VERSION 5.7 ;
  NOWIREEXTENSIONATPIN ON ;
  DIVIDERCHAR "/" ;
  BUSBITCHARS "[]" ;
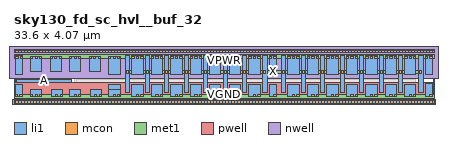
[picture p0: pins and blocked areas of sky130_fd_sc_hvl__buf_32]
MACRO sky130_fd_sc_hvl__buf_32
  CLASS BLOCK ;
  FOREIGN sky130_fd_sc_hvl__buf_32 ;
  ORIGIN 0.000 0.000 ;
  SIZE 33.600 BY 4.070 ;
  PIN A
    ANTENNAGATEAREA 11.250000 ;
    PORT
      LAYER li1 ;
        RECT 0.220 1.580 4.630 1.815 ;
    END
  END A
  PIN VGND
    USE GROUND ;
    PORT
      LAYER li1 ;
        RECT 0.110 0.425 0.645 1.410 ;
        RECT 7.580 1.025 8.480 1.395 ;
        RECT 1.340 0.415 2.230 1.025 ;
        RECT 2.960 0.425 3.855 1.025 ;
        RECT 4.440 0.425 5.330 1.025 ;
        RECT 6.080 0.425 6.975 1.025 ;
        RECT 7.560 0.425 8.480 1.025 ;
        RECT 9.430 0.425 10.320 1.395 ;
        RECT 10.990 0.425 11.880 1.395 ;
        RECT 12.550 0.425 13.440 1.395 ;
        RECT 14.110 0.425 15.000 1.395 ;
        RECT 15.670 0.425 16.560 1.395 ;
        RECT 17.230 0.425 18.120 1.395 ;
        RECT 18.790 0.425 19.680 1.395 ;
        RECT 20.430 0.425 20.960 1.395 ;
        RECT 21.910 0.425 22.800 1.395 ;
        RECT 23.470 0.425 24.360 1.395 ;
        RECT 25.030 0.425 25.920 1.395 ;
        RECT 26.590 0.425 27.480 1.395 ;
        RECT 28.150 0.425 29.040 1.395 ;
        RECT 29.710 0.425 30.600 1.395 ;
        RECT 31.270 0.425 32.160 1.395 ;
        RECT 32.910 0.425 33.440 1.495 ;
      LAYER mcon ;
        RECT 0.115 0.425 0.285 0.595 ;
        RECT 0.475 0.425 0.645 0.595 ;
        RECT 1.340 0.425 1.510 0.595 ;
        RECT 1.700 0.425 1.870 0.595 ;
        RECT 2.060 0.425 2.230 0.595 ;
        RECT 3.320 0.425 3.490 0.595 ;
        RECT 3.680 0.425 3.850 0.595 ;
        RECT 4.800 0.425 4.970 0.595 ;
        RECT 5.160 0.425 5.330 0.595 ;
        RECT 6.440 0.425 6.610 0.595 ;
        RECT 6.800 0.425 6.970 0.595 ;
        RECT 7.920 0.425 8.090 0.595 ;
        RECT 8.280 0.425 8.450 0.595 ;
        RECT 9.790 0.425 9.960 0.595 ;
        RECT 10.150 0.425 10.320 0.595 ;
        RECT 11.350 0.425 11.520 0.595 ;
        RECT 11.710 0.425 11.880 0.595 ;
        RECT 12.910 0.425 13.080 0.595 ;
        RECT 13.270 0.425 13.440 0.595 ;
        RECT 14.470 0.425 14.640 0.595 ;
        RECT 14.830 0.425 15.000 0.595 ;
        RECT 16.030 0.425 16.200 0.595 ;
        RECT 16.390 0.425 16.560 0.595 ;
        RECT 17.590 0.425 17.760 0.595 ;
        RECT 17.950 0.425 18.120 0.595 ;
        RECT 19.150 0.425 19.320 0.595 ;
        RECT 19.510 0.425 19.680 0.595 ;
        RECT 20.790 0.425 20.960 0.595 ;
        RECT 22.270 0.425 22.440 0.595 ;
        RECT 22.630 0.425 22.800 0.595 ;
        RECT 23.830 0.425 24.000 0.595 ;
        RECT 24.190 0.425 24.360 0.595 ;
        RECT 25.390 0.425 25.560 0.595 ;
        RECT 25.750 0.425 25.920 0.595 ;
        RECT 26.950 0.425 27.120 0.595 ;
        RECT 27.310 0.425 27.480 0.595 ;
        RECT 28.510 0.425 28.680 0.595 ;
        RECT 28.870 0.425 29.040 0.595 ;
        RECT 30.070 0.425 30.240 0.595 ;
        RECT 30.430 0.425 30.600 0.595 ;
        RECT 31.630 0.425 31.800 0.595 ;
        RECT 31.990 0.425 32.160 0.595 ;
        RECT 33.270 0.425 33.440 0.595 ;
      LAYER met1 ;
        RECT 0.000 0.255 33.600 0.625 ;
    END
  END VGND
  PIN VNB
    ANTENNADIFFAREA 5.712000 ;
    PORT
      LAYER pwell ;
        RECT 0.020 0.215 33.530 1.585 ;
        RECT -0.130 -0.215 33.730 0.215 ;
      LAYER li1 ;
        RECT 0.000 -0.085 33.600 0.085 ;
      LAYER mcon ;
        RECT 0.155 -0.085 0.325 0.085 ;
        RECT 0.635 -0.085 0.805 0.085 ;
        RECT 1.115 -0.085 1.285 0.085 ;
        RECT 1.595 -0.085 1.765 0.085 ;
        RECT 2.075 -0.085 2.245 0.085 ;
        RECT 2.555 -0.085 2.725 0.085 ;
        RECT 3.035 -0.085 3.205 0.085 ;
        RECT 3.515 -0.085 3.685 0.085 ;
        RECT 3.995 -0.085 4.165 0.085 ;
        RECT 4.475 -0.085 4.645 0.085 ;
        RECT 4.955 -0.085 5.125 0.085 ;
        RECT 5.435 -0.085 5.605 0.085 ;
        RECT 5.915 -0.085 6.085 0.085 ;
        RECT 6.395 -0.085 6.565 0.085 ;
        RECT 6.875 -0.085 7.045 0.085 ;
        RECT 7.355 -0.085 7.525 0.085 ;
        RECT 7.835 -0.085 8.005 0.085 ;
        RECT 8.315 -0.085 8.485 0.085 ;
        RECT 8.795 -0.085 8.965 0.085 ;
        RECT 9.275 -0.085 9.445 0.085 ;
        RECT 9.755 -0.085 9.925 0.085 ;
        RECT 10.235 -0.085 10.405 0.085 ;
        RECT 10.715 -0.085 10.885 0.085 ;
        RECT 11.195 -0.085 11.365 0.085 ;
        RECT 11.675 -0.085 11.845 0.085 ;
        RECT 12.155 -0.085 12.325 0.085 ;
        RECT 12.635 -0.085 12.805 0.085 ;
        RECT 13.115 -0.085 13.285 0.085 ;
        RECT 13.595 -0.085 13.765 0.085 ;
        RECT 14.075 -0.085 14.245 0.085 ;
        RECT 14.555 -0.085 14.725 0.085 ;
        RECT 15.035 -0.085 15.205 0.085 ;
        RECT 15.515 -0.085 15.685 0.085 ;
        RECT 15.995 -0.085 16.165 0.085 ;
        RECT 16.475 -0.085 16.645 0.085 ;
        RECT 16.955 -0.085 17.125 0.085 ;
        RECT 17.435 -0.085 17.605 0.085 ;
        RECT 17.915 -0.085 18.085 0.085 ;
        RECT 18.395 -0.085 18.565 0.085 ;
        RECT 18.875 -0.085 19.045 0.085 ;
        RECT 19.355 -0.085 19.525 0.085 ;
        RECT 19.835 -0.085 20.005 0.085 ;
        RECT 20.315 -0.085 20.485 0.085 ;
        RECT 20.795 -0.085 20.965 0.085 ;
        RECT 21.275 -0.085 21.445 0.085 ;
        RECT 21.755 -0.085 21.925 0.085 ;
        RECT 22.235 -0.085 22.405 0.085 ;
        RECT 22.715 -0.085 22.885 0.085 ;
        RECT 23.195 -0.085 23.365 0.085 ;
        RECT 23.675 -0.085 23.845 0.085 ;
        RECT 24.155 -0.085 24.325 0.085 ;
        RECT 24.635 -0.085 24.805 0.085 ;
        RECT 25.115 -0.085 25.285 0.085 ;
        RECT 25.595 -0.085 25.765 0.085 ;
        RECT 26.075 -0.085 26.245 0.085 ;
        RECT 26.555 -0.085 26.725 0.085 ;
        RECT 27.035 -0.085 27.205 0.085 ;
        RECT 27.515 -0.085 27.685 0.085 ;
        RECT 27.995 -0.085 28.165 0.085 ;
        RECT 28.475 -0.085 28.645 0.085 ;
        RECT 28.955 -0.085 29.125 0.085 ;
        RECT 29.435 -0.085 29.605 0.085 ;
        RECT 29.915 -0.085 30.085 0.085 ;
        RECT 30.395 -0.085 30.565 0.085 ;
        RECT 30.875 -0.085 31.045 0.085 ;
        RECT 31.355 -0.085 31.525 0.085 ;
        RECT 31.835 -0.085 32.005 0.085 ;
        RECT 32.315 -0.085 32.485 0.085 ;
        RECT 32.795 -0.085 32.965 0.085 ;
        RECT 33.275 -0.085 33.445 0.085 ;
      LAYER met1 ;
        RECT 0.000 -0.115 33.600 0.115 ;
    END
  END VNB
  PIN VPB
    ANTENNADIFFAREA 5.712000 ;
    PORT
      LAYER nwell ;
        RECT -0.330 1.885 33.930 4.485 ;
      LAYER li1 ;
        RECT 0.000 3.985 33.600 4.155 ;
      LAYER mcon ;
        RECT 0.155 3.985 0.325 4.155 ;
        RECT 0.635 3.985 0.805 4.155 ;
        RECT 1.115 3.985 1.285 4.155 ;
        RECT 1.595 3.985 1.765 4.155 ;
        RECT 2.075 3.985 2.245 4.155 ;
        RECT 2.555 3.985 2.725 4.155 ;
        RECT 3.035 3.985 3.205 4.155 ;
        RECT 3.515 3.985 3.685 4.155 ;
        RECT 3.995 3.985 4.165 4.155 ;
        RECT 4.475 3.985 4.645 4.155 ;
        RECT 4.955 3.985 5.125 4.155 ;
        RECT 5.435 3.985 5.605 4.155 ;
        RECT 5.915 3.985 6.085 4.155 ;
        RECT 6.395 3.985 6.565 4.155 ;
        RECT 6.875 3.985 7.045 4.155 ;
        RECT 7.355 3.985 7.525 4.155 ;
        RECT 7.835 3.985 8.005 4.155 ;
        RECT 8.315 3.985 8.485 4.155 ;
        RECT 8.795 3.985 8.965 4.155 ;
        RECT 9.275 3.985 9.445 4.155 ;
        RECT 9.755 3.985 9.925 4.155 ;
        RECT 10.235 3.985 10.405 4.155 ;
        RECT 10.715 3.985 10.885 4.155 ;
        RECT 11.195 3.985 11.365 4.155 ;
        RECT 11.675 3.985 11.845 4.155 ;
        RECT 12.155 3.985 12.325 4.155 ;
        RECT 12.635 3.985 12.805 4.155 ;
        RECT 13.115 3.985 13.285 4.155 ;
        RECT 13.595 3.985 13.765 4.155 ;
        RECT 14.075 3.985 14.245 4.155 ;
        RECT 14.555 3.985 14.725 4.155 ;
        RECT 15.035 3.985 15.205 4.155 ;
        RECT 15.515 3.985 15.685 4.155 ;
        RECT 15.995 3.985 16.165 4.155 ;
        RECT 16.475 3.985 16.645 4.155 ;
        RECT 16.955 3.985 17.125 4.155 ;
        RECT 17.435 3.985 17.605 4.155 ;
        RECT 17.915 3.985 18.085 4.155 ;
        RECT 18.395 3.985 18.565 4.155 ;
        RECT 18.875 3.985 19.045 4.155 ;
        RECT 19.355 3.985 19.525 4.155 ;
        RECT 19.835 3.985 20.005 4.155 ;
        RECT 20.315 3.985 20.485 4.155 ;
        RECT 20.795 3.985 20.965 4.155 ;
        RECT 21.275 3.985 21.445 4.155 ;
        RECT 21.755 3.985 21.925 4.155 ;
        RECT 22.235 3.985 22.405 4.155 ;
        RECT 22.715 3.985 22.885 4.155 ;
        RECT 23.195 3.985 23.365 4.155 ;
        RECT 23.675 3.985 23.845 4.155 ;
        RECT 24.155 3.985 24.325 4.155 ;
        RECT 24.635 3.985 24.805 4.155 ;
        RECT 25.115 3.985 25.285 4.155 ;
        RECT 25.595 3.985 25.765 4.155 ;
        RECT 26.075 3.985 26.245 4.155 ;
        RECT 26.555 3.985 26.725 4.155 ;
        RECT 27.035 3.985 27.205 4.155 ;
        RECT 27.515 3.985 27.685 4.155 ;
        RECT 27.995 3.985 28.165 4.155 ;
        RECT 28.475 3.985 28.645 4.155 ;
        RECT 28.955 3.985 29.125 4.155 ;
        RECT 29.435 3.985 29.605 4.155 ;
        RECT 29.915 3.985 30.085 4.155 ;
        RECT 30.395 3.985 30.565 4.155 ;
        RECT 30.875 3.985 31.045 4.155 ;
        RECT 31.355 3.985 31.525 4.155 ;
        RECT 31.835 3.985 32.005 4.155 ;
        RECT 32.315 3.985 32.485 4.155 ;
        RECT 32.795 3.985 32.965 4.155 ;
        RECT 33.275 3.985 33.445 4.155 ;
      LAYER met1 ;
        RECT 0.000 3.955 33.600 4.185 ;
    END
  END VPB
  PIN VPWR
    USE POWER ;
    PORT
      LAYER li1 ;
        RECT 0.110 2.175 0.680 3.755 ;
        RECT 1.340 2.445 2.230 3.675 ;
        RECT 2.880 2.445 3.770 3.675 ;
        RECT 4.460 2.445 5.350 3.675 ;
        RECT 6.000 2.445 6.890 3.675 ;
        RECT 7.580 2.235 8.480 3.675 ;
        RECT 9.430 2.175 10.320 3.755 ;
        RECT 10.990 2.175 11.880 3.755 ;
        RECT 12.550 2.175 13.440 3.755 ;
        RECT 14.110 2.175 15.000 3.755 ;
        RECT 15.670 2.175 16.560 3.755 ;
        RECT 17.230 2.175 18.120 3.755 ;
        RECT 18.790 2.175 19.680 3.755 ;
        RECT 20.430 2.175 20.960 3.755 ;
        RECT 21.910 2.175 22.800 3.755 ;
        RECT 23.470 2.175 24.360 3.755 ;
        RECT 25.030 2.175 25.920 3.755 ;
        RECT 26.590 2.175 27.480 3.755 ;
        RECT 28.150 2.175 29.040 3.755 ;
        RECT 29.710 2.175 30.600 3.755 ;
        RECT 31.270 2.175 32.160 3.755 ;
        RECT 32.910 2.175 33.440 3.755 ;
      LAYER mcon ;
        RECT 0.150 3.475 0.320 3.645 ;
        RECT 0.510 3.475 0.680 3.645 ;
        RECT 1.340 3.475 1.510 3.645 ;
        RECT 1.700 3.475 1.870 3.645 ;
        RECT 2.060 3.475 2.230 3.645 ;
        RECT 2.880 3.475 3.050 3.645 ;
        RECT 3.240 3.475 3.410 3.645 ;
        RECT 3.600 3.475 3.770 3.645 ;
        RECT 4.460 3.475 4.630 3.645 ;
        RECT 4.820 3.475 4.990 3.645 ;
        RECT 5.180 3.475 5.350 3.645 ;
        RECT 6.000 3.475 6.170 3.645 ;
        RECT 6.360 3.475 6.530 3.645 ;
        RECT 6.720 3.475 6.890 3.645 ;
        RECT 7.580 3.475 7.750 3.645 ;
        RECT 7.940 3.475 8.110 3.645 ;
        RECT 8.300 3.475 8.470 3.645 ;
        RECT 9.430 3.475 9.600 3.645 ;
        RECT 9.790 3.475 9.960 3.645 ;
        RECT 10.150 3.475 10.320 3.645 ;
        RECT 10.990 3.475 11.160 3.645 ;
        RECT 11.350 3.475 11.520 3.645 ;
        RECT 11.710 3.475 11.880 3.645 ;
        RECT 12.550 3.475 12.720 3.645 ;
        RECT 12.910 3.475 13.080 3.645 ;
        RECT 13.270 3.475 13.440 3.645 ;
        RECT 14.110 3.475 14.280 3.645 ;
        RECT 14.470 3.475 14.640 3.645 ;
        RECT 14.830 3.475 15.000 3.645 ;
        RECT 15.670 3.475 15.840 3.645 ;
        RECT 16.030 3.475 16.200 3.645 ;
        RECT 16.390 3.475 16.560 3.645 ;
        RECT 17.230 3.475 17.400 3.645 ;
        RECT 17.590 3.475 17.760 3.645 ;
        RECT 17.950 3.475 18.120 3.645 ;
        RECT 18.790 3.475 18.960 3.645 ;
        RECT 19.150 3.475 19.320 3.645 ;
        RECT 19.510 3.475 19.680 3.645 ;
        RECT 20.430 3.475 20.600 3.645 ;
        RECT 20.790 3.475 20.960 3.645 ;
        RECT 21.910 3.475 22.080 3.645 ;
        RECT 22.270 3.475 22.440 3.645 ;
        RECT 22.630 3.475 22.800 3.645 ;
        RECT 23.470 3.475 23.640 3.645 ;
        RECT 23.830 3.475 24.000 3.645 ;
        RECT 24.190 3.475 24.360 3.645 ;
        RECT 25.030 3.475 25.200 3.645 ;
        RECT 25.390 3.475 25.560 3.645 ;
        RECT 25.750 3.475 25.920 3.645 ;
        RECT 26.590 3.475 26.760 3.645 ;
        RECT 26.950 3.475 27.120 3.645 ;
        RECT 27.310 3.475 27.480 3.645 ;
        RECT 28.150 3.475 28.320 3.645 ;
        RECT 28.510 3.475 28.680 3.645 ;
        RECT 28.870 3.475 29.040 3.645 ;
        RECT 29.710 3.475 29.880 3.645 ;
        RECT 30.070 3.475 30.240 3.645 ;
        RECT 30.430 3.475 30.600 3.645 ;
        RECT 31.270 3.475 31.440 3.645 ;
        RECT 31.630 3.475 31.800 3.645 ;
        RECT 31.990 3.475 32.160 3.645 ;
        RECT 32.910 3.475 33.080 3.645 ;
        RECT 33.270 3.475 33.440 3.645 ;
      LAYER met1 ;
        RECT 0.000 3.445 33.600 3.815 ;
    END
  END VPWR
  PIN X
    ANTENNADIFFAREA 10.080000 ;
    PORT
      LAYER li1 ;
        RECT 8.930 0.790 9.260 3.755 ;
        RECT 10.490 0.790 10.820 3.755 ;
        RECT 12.050 0.790 12.380 3.755 ;
        RECT 13.610 0.790 13.940 3.755 ;
        RECT 15.170 0.790 15.500 3.755 ;
        RECT 16.730 0.790 17.060 3.755 ;
        RECT 18.290 0.790 18.620 3.755 ;
        RECT 19.850 0.790 20.260 3.755 ;
        RECT 21.410 0.790 21.740 3.755 ;
        RECT 22.970 0.790 23.300 3.755 ;
        RECT 24.530 0.790 24.860 3.755 ;
        RECT 26.090 0.790 26.420 3.755 ;
        RECT 27.650 0.790 27.980 3.755 ;
        RECT 29.210 0.790 29.540 3.755 ;
        RECT 30.770 0.790 31.100 3.755 ;
        RECT 32.330 0.790 32.740 3.755 ;
      LAYER mcon ;
        RECT 9.010 2.320 9.180 2.490 ;
        RECT 10.570 2.320 10.740 2.490 ;
        RECT 12.130 2.320 12.300 2.490 ;
        RECT 13.690 2.320 13.860 2.490 ;
        RECT 15.250 2.320 15.420 2.490 ;
        RECT 16.810 2.320 16.980 2.490 ;
        RECT 18.370 2.320 18.540 2.490 ;
        RECT 19.930 2.320 20.100 2.490 ;
        RECT 21.490 2.320 21.660 2.490 ;
        RECT 23.050 2.320 23.220 2.490 ;
        RECT 24.610 2.320 24.780 2.490 ;
        RECT 26.170 2.320 26.340 2.490 ;
        RECT 27.730 2.320 27.900 2.490 ;
        RECT 29.290 2.320 29.460 2.490 ;
        RECT 30.850 2.320 31.020 2.490 ;
        RECT 32.410 2.320 32.580 2.490 ;
      LAYER met1 ;
        RECT 8.950 2.290 32.640 2.520 ;
    END
  END X
  OBS
      LAYER li1 ;
        RECT 0.850 2.265 1.160 3.755 ;
        RECT 2.400 2.265 2.710 3.755 ;
        RECT 3.940 2.265 4.290 3.755 ;
        RECT 5.520 2.265 5.830 3.755 ;
        RECT 7.060 2.265 7.410 3.755 ;
        RECT 0.850 1.985 7.410 2.265 ;
        RECT 4.800 1.410 7.410 1.985 ;
        RECT 9.520 1.565 10.190 1.895 ;
        RECT 11.080 1.565 11.750 1.895 ;
        RECT 12.640 1.565 13.310 1.895 ;
        RECT 14.200 1.565 14.870 1.895 ;
        RECT 15.760 1.565 16.430 1.895 ;
        RECT 17.320 1.565 17.990 1.895 ;
        RECT 18.880 1.565 19.550 1.895 ;
        RECT 20.430 1.565 21.100 1.895 ;
        RECT 22.000 1.565 22.670 1.895 ;
        RECT 23.560 1.565 24.230 1.895 ;
        RECT 25.120 1.565 25.790 1.895 ;
        RECT 26.680 1.565 27.350 1.895 ;
        RECT 28.240 1.565 28.910 1.895 ;
        RECT 29.800 1.565 30.470 1.895 ;
        RECT 31.360 1.565 32.030 1.895 ;
        RECT 0.815 1.195 7.410 1.410 ;
        RECT 0.815 0.755 1.170 1.195 ;
        RECT 2.400 0.730 2.790 1.195 ;
        RECT 4.025 0.730 4.270 1.195 ;
        RECT 5.520 0.730 5.910 1.195 ;
        RECT 7.145 0.730 7.390 1.195 ;
      LAYER mcon ;
        RECT 5.020 1.580 5.190 1.750 ;
        RECT 5.380 1.580 5.550 1.750 ;
        RECT 5.740 1.580 5.910 1.750 ;
        RECT 6.100 1.580 6.270 1.750 ;
        RECT 6.460 1.580 6.630 1.750 ;
        RECT 6.820 1.580 6.990 1.750 ;
        RECT 7.180 1.580 7.350 1.750 ;
        RECT 9.590 1.580 9.760 1.750 ;
        RECT 9.950 1.580 10.120 1.750 ;
        RECT 11.150 1.580 11.320 1.750 ;
        RECT 11.510 1.580 11.680 1.750 ;
        RECT 12.710 1.580 12.880 1.750 ;
        RECT 13.070 1.580 13.240 1.750 ;
        RECT 14.270 1.580 14.440 1.750 ;
        RECT 14.630 1.580 14.800 1.750 ;
        RECT 15.830 1.580 16.000 1.750 ;
        RECT 16.190 1.580 16.360 1.750 ;
        RECT 17.390 1.580 17.560 1.750 ;
        RECT 17.750 1.580 17.920 1.750 ;
        RECT 18.950 1.580 19.120 1.750 ;
        RECT 19.310 1.580 19.480 1.750 ;
        RECT 20.500 1.580 20.670 1.750 ;
        RECT 20.860 1.580 21.030 1.750 ;
        RECT 22.070 1.580 22.240 1.750 ;
        RECT 22.430 1.580 22.600 1.750 ;
        RECT 23.630 1.580 23.800 1.750 ;
        RECT 23.990 1.580 24.160 1.750 ;
        RECT 25.190 1.580 25.360 1.750 ;
        RECT 25.550 1.580 25.720 1.750 ;
        RECT 26.750 1.580 26.920 1.750 ;
        RECT 27.110 1.580 27.280 1.750 ;
        RECT 28.310 1.580 28.480 1.750 ;
        RECT 28.670 1.580 28.840 1.750 ;
        RECT 29.870 1.580 30.040 1.750 ;
        RECT 30.230 1.580 30.400 1.750 ;
        RECT 31.430 1.580 31.600 1.750 ;
        RECT 31.790 1.580 31.960 1.750 ;
      LAYER met1 ;
        RECT 4.960 1.550 32.090 1.780 ;
  END
END sky130_fd_sc_hvl__buf_32
END LIBRARY

